One B-rep face of a CAD part: STEP entity #2256.
In plain terms, the cylindrical face has radius 140.44 mm (diameter 280.881 mm), a partial arc.
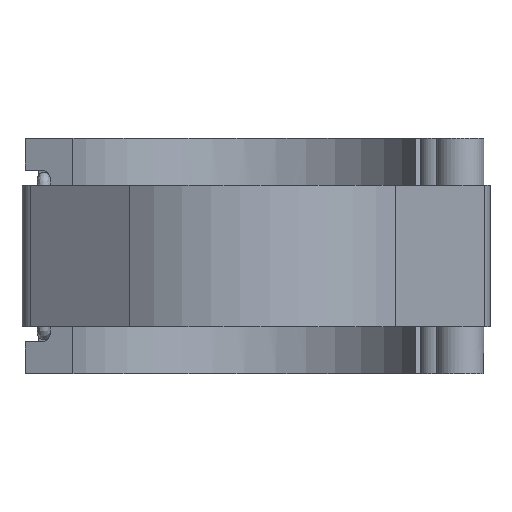
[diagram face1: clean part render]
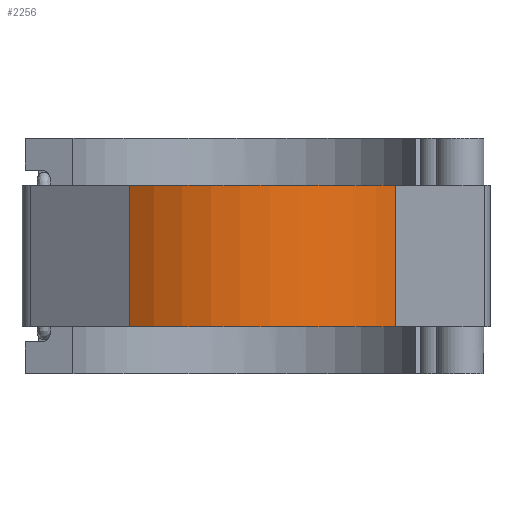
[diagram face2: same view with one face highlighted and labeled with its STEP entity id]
Its self-contained STEP definition (entity closure, numbers rounded to 3 decimals):
#216=FACE_OUTER_BOUND('',#351,.T.);
#351=EDGE_LOOP('',(#1991,#1992,#1993,#1994));
#447=CIRCLE('',#2420,140.441);
#453=CIRCLE('',#2427,140.441);
#703=LINE('',#4133,#891);
#708=LINE('',#4141,#896);
#891=VECTOR('',#3103,10.);
#896=VECTOR('',#3114,10.);
#1022=VERTEX_POINT('',#3820);
#1023=VERTEX_POINT('',#3822);
#1029=VERTEX_POINT('',#3839);
#1030=VERTEX_POINT('',#3841);
#1275=EDGE_CURVE('',#1022,#1023,#447,.T.);
#1286=EDGE_CURVE('',#1029,#1030,#453,.T.);
#1403=EDGE_CURVE('',#1029,#1023,#703,.T.);
#1408=EDGE_CURVE('',#1022,#1030,#708,.T.);
#1991=ORIENTED_EDGE('',*,*,#1408,.T.);
#1992=ORIENTED_EDGE('',*,*,#1286,.F.);
#1993=ORIENTED_EDGE('',*,*,#1403,.T.);
#1994=ORIENTED_EDGE('',*,*,#1275,.F.);
#2144=CYLINDRICAL_SURFACE('',#2500,140.441);
#2256=ADVANCED_FACE('',(#216),#2144,.T.);
#2420=AXIS2_PLACEMENT_3D('',#3823,#2862,#2863);
#2427=AXIS2_PLACEMENT_3D('',#3842,#2881,#2882);
#2500=AXIS2_PLACEMENT_3D('',#4142,#3115,#3116);
#2862=DIRECTION('center_axis',(0.,0.,-1.));
#2863=DIRECTION('ref_axis',(0.611,0.791,0.));
#2881=DIRECTION('center_axis',(0.,0.,1.));
#2882=DIRECTION('ref_axis',(0.611,0.791,0.));
#3103=DIRECTION('',(0.,0.,-1.));
#3114=DIRECTION('',(0.,0.,1.));
#3115=DIRECTION('center_axis',(0.,0.,1.));
#3116=DIRECTION('ref_axis',(0.611,0.791,0.));
#3820=CARTESIAN_POINT('',(113.201,-83.121,-52.807));
#3822=CARTESIAN_POINT('',(-85.876,-111.126,-52.807));
#3823=CARTESIAN_POINT('Origin',(0.,0.,
-52.807));
#3839=CARTESIAN_POINT('',(-85.876,-111.126,52.807));
#3841=CARTESIAN_POINT('',(113.201,-83.121,52.807));
#3842=CARTESIAN_POINT('Origin',(0.,0.,
52.807));
#4133=CARTESIAN_POINT('',(-85.876,-111.126,0.));
#4141=CARTESIAN_POINT('',(113.201,-83.121,0.));
#4142=CARTESIAN_POINT('Origin',(0.,0.,
0.));
